VERSION 5.7 ;
  NOWIREEXTENSIONATPIN ON ;
  DIVIDERCHAR "/" ;
  BUSBITCHARS "[]" ;
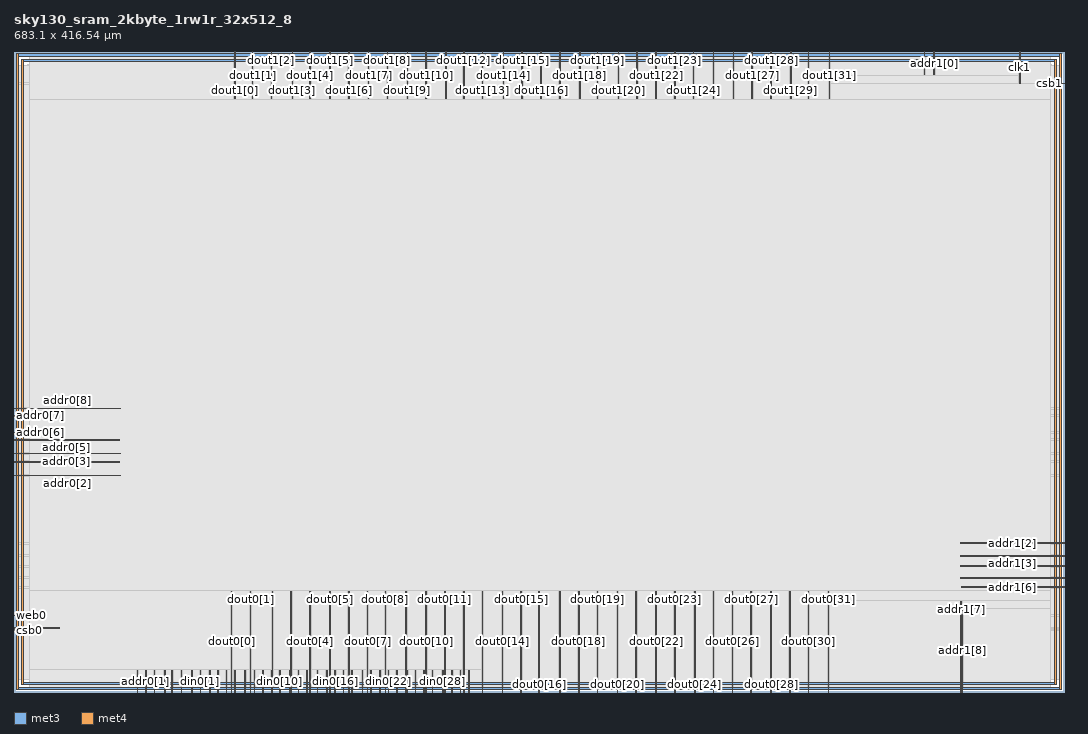
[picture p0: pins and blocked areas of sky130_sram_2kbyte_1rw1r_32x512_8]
MACRO sky130_sram_2kbyte_1rw1r_32x512_8
  CLASS BLOCK ;
  FOREIGN sky130_sram_2kbyte_1rw1r_32x512_8 ;
  ORIGIN 0.000 0.000 ;
  SIZE 683.100 BY 416.540 ;
  SYMMETRY X Y R90 ;
  PIN csb0
    DIRECTION INPUT ;
    ANTENNAGATEAREA 0.600000 ;
    PORT
      LAYER met3 ;
        RECT 0.000 40.120 14.660 40.500 ;
    END
  END csb0
  PIN web0
    DIRECTION INPUT ;
    ANTENNAGATEAREA 0.600000 ;
    PORT
      LAYER met3 ;
        RECT 0.000 49.640 14.660 50.020 ;
    END
  END web0
  PIN clk0
    DIRECTION INPUT ;
    ANTENNAGATEAREA 0.222000 ;
    PORT
      LAYER met3 ;
        RECT 0.000 41.480 29.875 41.860 ;
    END
  END clk0
  PIN addr0[2]
    DIRECTION INPUT ;
    ANTENNAGATEAREA 0.600000 ;
    PORT
      LAYER met3 ;
        RECT 0.000 140.760 69.060 141.140 ;
    END
  END addr0[2]
  PIN addr0[3]
    DIRECTION INPUT ;
    ANTENNAGATEAREA 0.600000 ;
    PORT
      LAYER met3 ;
        RECT 0.000 149.600 68.340 149.980 ;
    END
  END addr0[3]
  PIN addr0[4]
    DIRECTION INPUT ;
    ANTENNAGATEAREA 0.600000 ;
    PORT
      LAYER met3 ;
        RECT 0.000 155.040 69.060 155.420 ;
    END
  END addr0[4]
  PIN addr0[5]
    DIRECTION INPUT ;
    ANTENNAGATEAREA 0.600000 ;
    PORT
      LAYER met3 ;
        RECT 0.000 163.880 68.340 164.260 ;
    END
  END addr0[5]
  PIN addr0[6]
    DIRECTION INPUT ;
    ANTENNAGATEAREA 0.600000 ;
    PORT
      LAYER met3 ;
        RECT 0.000 168.640 10.580 169.020 ;
    END
  END addr0[6]
  PIN addr0[7]
    DIRECTION INPUT ;
    ANTENNAGATEAREA 0.600000 ;
    PORT
      LAYER met3 ;
        RECT 0.000 179.520 10.580 179.900 ;
    END
  END addr0[7]
  PIN addr0[8]
    DIRECTION INPUT ;
    ANTENNAGATEAREA 0.600000 ;
    PORT
      LAYER met3 ;
        RECT 0.000 184.280 69.060 184.660 ;
    END
  END addr0[8]
  PIN csb1
    DIRECTION INPUT ;
    ANTENNAGATEAREA 0.600000 ;
    PORT
      LAYER met3 ;
        RECT 669.700 395.760 683.100 396.140 ;
    END
  END csb1
  PIN addr1[2]
    DIRECTION INPUT ;
    ANTENNAGATEAREA 0.600000 ;
    PORT
      LAYER met3 ;
        RECT 616.080 96.560 683.100 96.940 ;
    END
  END addr1[2]
  PIN addr1[3]
    DIRECTION INPUT ;
    ANTENNAGATEAREA 0.600000 ;
    PORT
      LAYER met3 ;
        RECT 616.080 88.400 683.100 88.780 ;
    END
  END addr1[3]
  PIN addr1[4]
    DIRECTION INPUT ;
    ANTENNAGATEAREA 0.600000 ;
    PORT
      LAYER met3 ;
        RECT 616.080 81.600 683.100 81.980 ;
    END
  END addr1[4]
  PIN addr1[5]
    DIRECTION INPUT ;
    ANTENNAGATEAREA 0.600000 ;
    PORT
      LAYER met3 ;
        RECT 616.080 74.120 683.100 74.500 ;
    END
  END addr1[5]
  PIN addr1[6]
    DIRECTION INPUT ;
    ANTENNAGATEAREA 0.600000 ;
    PORT
      LAYER met3 ;
        RECT 616.630 68.000 683.100 68.380 ;
    END
  END addr1[6]
  PIN vccd1
    DIRECTION INOUT ;
    USE POWER ;
    SHAPE ABUTMENT ;
    PORT
      LAYER met3 ;
        RECT 4.760 410.040 678.340 411.780 ;
    END
    PORT
      LAYER met3 ;
        RECT 4.760 4.760 678.340 6.500 ;
    END
    PORT
      LAYER met4 ;
        RECT 4.760 4.760 6.500 411.780 ;
    END
    PORT
      LAYER met4 ;
        RECT 676.600 4.760 678.340 411.780 ;
    END
  END vccd1
  PIN vssd1
    DIRECTION INOUT ;
    USE GROUND ;
    SHAPE ABUTMENT ;
    PORT
      LAYER met3 ;
        RECT 1.360 1.360 681.740 3.100 ;
    END
    PORT
      LAYER met3 ;
        RECT 1.360 413.440 681.740 415.180 ;
    END
    PORT
      LAYER met4 ;
        RECT 1.360 1.360 3.100 415.180 ;
    END
    PORT
      LAYER met4 ;
        RECT 680.000 1.360 681.740 415.180 ;
    END
  END vssd1
  PIN clk1
    DIRECTION INPUT ;
    ANTENNAGATEAREA 0.222000 ;
    PORT
      LAYER met4 ;
        RECT 654.160 396.110 654.540 416.540 ;
    END
  END clk1
  PIN dout1[16]
    DIRECTION OUTPUT ;
    ANTENNADIFFAREA 0.553900 ;
    PORT
      LAYER met4 ;
        RECT 342.720 385.910 343.100 416.540 ;
    END
  END dout1[16]
  PIN dout1[17]
    DIRECTION OUTPUT ;
    ANTENNADIFFAREA 0.553900 ;
    PORT
      LAYER met4 ;
        RECT 354.960 385.910 355.340 416.540 ;
    END
  END dout1[17]
  PIN dout1[18]
    DIRECTION OUTPUT ;
    ANTENNADIFFAREA 0.553900 ;
    PORT
      LAYER met4 ;
        RECT 367.880 385.910 368.260 416.540 ;
    END
  END dout1[18]
  PIN dout1[19]
    DIRECTION OUTPUT ;
    ANTENNADIFFAREA 0.553900 ;
    PORT
      LAYER met4 ;
        RECT 379.440 385.910 379.820 416.540 ;
    END
  END dout1[19]
  PIN dout1[20]
    DIRECTION OUTPUT ;
    ANTENNADIFFAREA 0.553900 ;
    PORT
      LAYER met4 ;
        RECT 393.040 385.910 393.420 416.540 ;
    END
  END dout1[20]
  PIN dout1[21]
    DIRECTION OUTPUT ;
    ANTENNADIFFAREA 0.553900 ;
    PORT
      LAYER met4 ;
        RECT 405.280 385.910 405.660 416.540 ;
    END
  END dout1[21]
  PIN dout1[22]
    DIRECTION OUTPUT ;
    ANTENNADIFFAREA 0.553900 ;
    PORT
      LAYER met4 ;
        RECT 417.520 385.910 417.900 416.540 ;
    END
  END dout1[22]
  PIN dout1[23]
    DIRECTION OUTPUT ;
    ANTENNADIFFAREA 0.553900 ;
    PORT
      LAYER met4 ;
        RECT 429.760 385.910 430.140 416.540 ;
    END
  END dout1[23]
  PIN dout1[24]
    DIRECTION OUTPUT ;
    ANTENNADIFFAREA 0.553900 ;
    PORT
      LAYER met4 ;
        RECT 442.000 385.910 442.380 416.540 ;
    END
  END dout1[24]
  PIN dout1[25]
    DIRECTION OUTPUT ;
    ANTENNADIFFAREA 0.553900 ;
    PORT
      LAYER met4 ;
        RECT 454.920 385.910 455.300 416.540 ;
    END
  END dout1[25]
  PIN dout1[26]
    DIRECTION OUTPUT ;
    ANTENNADIFFAREA 0.553900 ;
    PORT
      LAYER met4 ;
        RECT 467.840 385.910 468.220 416.540 ;
    END
  END dout1[26]
  PIN dout1[27]
    DIRECTION OUTPUT ;
    ANTENNADIFFAREA 0.553900 ;
    PORT
      LAYER met4 ;
        RECT 480.080 385.910 480.460 416.540 ;
    END
  END dout1[27]
  PIN dout1[28]
    DIRECTION OUTPUT ;
    ANTENNADIFFAREA 0.553900 ;
    PORT
      LAYER met4 ;
        RECT 492.320 385.910 492.700 416.540 ;
    END
  END dout1[28]
  PIN dout1[29]
    DIRECTION OUTPUT ;
    ANTENNADIFFAREA 0.553900 ;
    PORT
      LAYER met4 ;
        RECT 505.240 385.910 505.620 416.540 ;
    END
  END dout1[29]
  PIN dout1[30]
    DIRECTION OUTPUT ;
    ANTENNADIFFAREA 0.553900 ;
    PORT
      LAYER met4 ;
        RECT 516.800 385.910 517.180 416.540 ;
    END
  END dout1[30]
  PIN dout1[31]
    DIRECTION OUTPUT ;
    ANTENNADIFFAREA 0.553900 ;
    PORT
      LAYER met4 ;
        RECT 530.400 385.910 530.780 416.540 ;
    END
  END dout1[31]
  PIN addr1[0]
    DIRECTION INPUT ;
    ANTENNAGATEAREA 0.600000 ;
    PORT
      LAYER met4 ;
        RECT 598.400 401.550 598.780 416.540 ;
    END
  END addr1[0]
  PIN addr1[1]
    DIRECTION INPUT ;
    ANTENNAGATEAREA 0.600000 ;
    PORT
      LAYER met4 ;
        RECT 592.280 401.550 592.660 416.540 ;
    END
  END addr1[1]
  PIN dout1[2]
    DIRECTION OUTPUT ;
    ANTENNADIFFAREA 0.553900 ;
    PORT
      LAYER met4 ;
        RECT 167.280 385.910 167.660 416.540 ;
    END
  END dout1[2]
  PIN dout1[3]
    DIRECTION OUTPUT ;
    ANTENNADIFFAREA 0.553900 ;
    PORT
      LAYER met4 ;
        RECT 180.880 385.910 181.260 416.540 ;
    END
  END dout1[3]
  PIN dout1[4]
    DIRECTION OUTPUT ;
    ANTENNADIFFAREA 0.553900 ;
    PORT
      LAYER met4 ;
        RECT 192.440 385.910 192.820 416.540 ;
    END
  END dout1[4]
  PIN dout1[5]
    DIRECTION OUTPUT ;
    ANTENNADIFFAREA 0.553900 ;
    PORT
      LAYER met4 ;
        RECT 205.360 385.910 205.740 416.540 ;
    END
  END dout1[5]
  PIN dout1[6]
    DIRECTION OUTPUT ;
    ANTENNADIFFAREA 0.553900 ;
    PORT
      LAYER met4 ;
        RECT 217.600 385.910 217.980 416.540 ;
    END
  END dout1[6]
  PIN dout1[7]
    DIRECTION OUTPUT ;
    ANTENNADIFFAREA 0.553900 ;
    PORT
      LAYER met4 ;
        RECT 230.520 385.910 230.900 416.540 ;
    END
  END dout1[7]
  PIN dout1[8]
    DIRECTION OUTPUT ;
    ANTENNADIFFAREA 0.553900 ;
    PORT
      LAYER met4 ;
        RECT 242.760 385.910 243.140 416.540 ;
    END
  END dout1[8]
  PIN dout1[9]
    DIRECTION OUTPUT ;
    ANTENNADIFFAREA 0.553900 ;
    PORT
      LAYER met4 ;
        RECT 255.680 385.910 256.060 416.540 ;
    END
  END dout1[9]
  PIN dout1[10]
    DIRECTION OUTPUT ;
    ANTENNADIFFAREA 0.553900 ;
    PORT
      LAYER met4 ;
        RECT 267.920 385.910 268.300 416.540 ;
    END
  END dout1[10]
  PIN dout1[11]
    DIRECTION OUTPUT ;
    ANTENNADIFFAREA 0.553900 ;
    PORT
      LAYER met4 ;
        RECT 280.840 385.910 281.220 416.540 ;
    END
  END dout1[11]
  PIN dout1[12]
    DIRECTION OUTPUT ;
    ANTENNADIFFAREA 0.553900 ;
    PORT
      LAYER met4 ;
        RECT 292.400 385.910 292.780 416.540 ;
    END
  END dout1[12]
  PIN dout1[13]
    DIRECTION OUTPUT ;
    ANTENNADIFFAREA 0.553900 ;
    PORT
      LAYER met4 ;
        RECT 304.640 385.910 305.020 416.540 ;
    END
  END dout1[13]
  PIN dout1[14]
    DIRECTION OUTPUT ;
    ANTENNADIFFAREA 0.553900 ;
    PORT
      LAYER met4 ;
        RECT 318.240 385.910 318.620 416.540 ;
    END
  END dout1[14]
  PIN dout1[15]
    DIRECTION OUTPUT ;
    ANTENNADIFFAREA 0.553900 ;
    PORT
      LAYER met4 ;
        RECT 330.480 385.910 330.860 416.540 ;
    END
  END dout1[15]
  PIN dout1[0]
    DIRECTION OUTPUT ;
    ANTENNADIFFAREA 0.553900 ;
    PORT
      LAYER met4 ;
        RECT 143.480 385.910 143.860 416.540 ;
    END
  END dout1[0]
  PIN dout1[1]
    DIRECTION OUTPUT ;
    ANTENNADIFFAREA 0.553900 ;
    PORT
      LAYER met4 ;
        RECT 155.040 385.910 155.420 416.540 ;
    END
  END dout1[1]
  PIN dout0[3]
    DIRECTION OUTPUT ;
    ANTENNADIFFAREA 0.553900 ;
    PORT
      LAYER met4 ;
        RECT 180.200 0.000 180.580 65.310 ;
    END
  END dout0[3]
  PIN dout0[4]
    DIRECTION OUTPUT ;
    ANTENNADIFFAREA 0.553900 ;
    PORT
      LAYER met4 ;
        RECT 192.440 0.000 192.820 65.310 ;
    END
  END dout0[4]
  PIN dout0[5]
    DIRECTION OUTPUT ;
    ANTENNADIFFAREA 0.553900 ;
    PORT
      LAYER met4 ;
        RECT 205.360 0.000 205.740 65.310 ;
    END
  END dout0[5]
  PIN dout0[6]
    DIRECTION OUTPUT ;
    ANTENNADIFFAREA 0.553900 ;
    PORT
      LAYER met4 ;
        RECT 217.600 0.000 217.980 65.310 ;
    END
  END dout0[6]
  PIN dout0[7]
    DIRECTION OUTPUT ;
    ANTENNADIFFAREA 0.553900 ;
    PORT
      LAYER met4 ;
        RECT 229.840 0.000 230.220 65.310 ;
    END
  END dout0[7]
  PIN dout0[8]
    DIRECTION OUTPUT ;
    ANTENNADIFFAREA 0.553900 ;
    PORT
      LAYER met4 ;
        RECT 241.400 0.000 241.780 65.310 ;
    END
  END dout0[8]
  PIN dout0[9]
    DIRECTION OUTPUT ;
    ANTENNADIFFAREA 0.553900 ;
    PORT
      LAYER met4 ;
        RECT 255.000 0.000 255.380 65.310 ;
    END
  END dout0[9]
  PIN dout0[10]
    DIRECTION OUTPUT ;
    ANTENNADIFFAREA 0.553900 ;
    PORT
      LAYER met4 ;
        RECT 267.920 0.000 268.300 65.310 ;
    END
  END dout0[10]
  PIN dout0[11]
    DIRECTION OUTPUT ;
    ANTENNADIFFAREA 0.553900 ;
    PORT
      LAYER met4 ;
        RECT 280.160 0.000 280.540 65.310 ;
    END
  END dout0[11]
  PIN dout0[12]
    DIRECTION OUTPUT ;
    ANTENNADIFFAREA 0.553900 ;
    PORT
      LAYER met4 ;
        RECT 292.400 0.000 292.780 65.310 ;
    END
  END dout0[12]
  PIN dout0[13]
    DIRECTION OUTPUT ;
    ANTENNADIFFAREA 0.553900 ;
    PORT
      LAYER met4 ;
        RECT 304.640 0.000 305.020 65.310 ;
    END
  END dout0[13]
  PIN dout0[14]
    DIRECTION OUTPUT ;
    ANTENNADIFFAREA 0.553900 ;
    PORT
      LAYER met4 ;
        RECT 317.560 0.000 317.940 65.310 ;
    END
  END dout0[14]
  PIN dout0[15]
    DIRECTION OUTPUT ;
    ANTENNADIFFAREA 0.553900 ;
    PORT
      LAYER met4 ;
        RECT 329.800 0.000 330.180 65.310 ;
    END
  END dout0[15]
  PIN dout0[16]
    DIRECTION OUTPUT ;
    ANTENNADIFFAREA 0.553900 ;
    PORT
      LAYER met4 ;
        RECT 341.360 0.000 341.740 65.310 ;
    END
  END dout0[16]
  PIN addr0[0]
    DIRECTION INPUT ;
    ANTENNAGATEAREA 0.600000 ;
    PORT
      LAYER met4 ;
        RECT 80.240 0.000 80.620 14.310 ;
    END
  END addr0[0]
  PIN addr0[1]
    DIRECTION INPUT ;
    ANTENNAGATEAREA 0.600000 ;
    PORT
      LAYER met4 ;
        RECT 85.680 0.000 86.060 14.310 ;
    END
  END addr0[1]
  PIN wmask0[0]
    DIRECTION INPUT ;
    ANTENNAGATEAREA 0.600000 ;
    PORT
      LAYER met4 ;
        RECT 91.120 0.000 91.500 14.310 ;
    END
  END wmask0[0]
  PIN wmask0[1]
    DIRECTION INPUT ;
    ANTENNAGATEAREA 0.600000 ;
    PORT
      LAYER met4 ;
        RECT 97.920 0.000 98.300 14.310 ;
    END
  END wmask0[1]
  PIN wmask0[2]
    DIRECTION INPUT ;
    ANTENNAGATEAREA 0.600000 ;
    PORT
      LAYER met4 ;
        RECT 102.680 0.000 103.060 14.310 ;
    END
  END wmask0[2]
  PIN wmask0[3]
    DIRECTION INPUT ;
    ANTENNAGATEAREA 0.600000 ;
    PORT
      LAYER met4 ;
        RECT 108.800 0.000 109.180 14.310 ;
    END
  END wmask0[3]
  PIN din0[0]
    DIRECTION INPUT ;
    ANTENNAGATEAREA 0.600000 ;
    PORT
      LAYER met4 ;
        RECT 115.600 0.000 115.980 14.310 ;
    END
  END din0[0]
  PIN din0[1]
    DIRECTION INPUT ;
    ANTENNAGATEAREA 0.600000 ;
    PORT
      LAYER met4 ;
        RECT 121.040 0.000 121.420 14.310 ;
    END
  END din0[1]
  PIN din0[2]
    DIRECTION INPUT ;
    ANTENNAGATEAREA 0.600000 ;
    PORT
      LAYER met4 ;
        RECT 127.160 0.000 127.540 14.310 ;
    END
  END din0[2]
  PIN din0[3]
    DIRECTION INPUT ;
    ANTENNAGATEAREA 0.600000 ;
    PORT
      LAYER met4 ;
        RECT 132.600 0.000 132.980 14.310 ;
    END
  END din0[3]
  PIN din0[4]
    DIRECTION INPUT ;
    ANTENNAGATEAREA 0.600000 ;
    PORT
      LAYER met4 ;
        RECT 138.040 0.000 138.420 14.310 ;
    END
  END din0[4]
  PIN din0[5]
    DIRECTION INPUT ;
    ANTENNAGATEAREA 0.600000 ;
    PORT
      LAYER met4 ;
        RECT 143.480 0.000 143.860 14.310 ;
    END
  END din0[5]
  PIN din0[6]
    DIRECTION INPUT ;
    ANTENNAGATEAREA 0.600000 ;
    PORT
      LAYER met4 ;
        RECT 150.280 0.000 150.660 14.310 ;
    END
  END din0[6]
  PIN din0[7]
    DIRECTION INPUT ;
    ANTENNAGATEAREA 0.600000 ;
    PORT
      LAYER met4 ;
        RECT 156.400 0.000 156.780 14.310 ;
    END
  END din0[7]
  PIN din0[8]
    DIRECTION INPUT ;
    ANTENNAGATEAREA 0.600000 ;
    PORT
      LAYER met4 ;
        RECT 161.840 0.000 162.220 14.310 ;
    END
  END din0[8]
  PIN din0[9]
    DIRECTION INPUT ;
    ANTENNAGATEAREA 0.600000 ;
    PORT
      LAYER met4 ;
        RECT 167.280 0.000 167.660 14.310 ;
    END
  END din0[9]
  PIN din0[10]
    DIRECTION INPUT ;
    ANTENNAGATEAREA 0.600000 ;
    PORT
      LAYER met4 ;
        RECT 172.720 0.000 173.100 14.310 ;
    END
  END din0[10]
  PIN din0[11]
    DIRECTION INPUT ;
    ANTENNAGATEAREA 0.600000 ;
    PORT
      LAYER met4 ;
        RECT 179.520 0.000 179.900 14.310 ;
    END
  END din0[11]
  PIN din0[12]
    DIRECTION INPUT ;
    ANTENNAGATEAREA 0.600000 ;
    PORT
      LAYER met4 ;
        RECT 184.960 0.000 185.340 14.310 ;
    END
  END din0[12]
  PIN din0[13]
    DIRECTION INPUT ;
    ANTENNAGATEAREA 0.600000 ;
    PORT
      LAYER met4 ;
        RECT 190.400 0.000 190.780 14.310 ;
    END
  END din0[13]
  PIN din0[14]
    DIRECTION INPUT ;
    ANTENNAGATEAREA 0.600000 ;
    PORT
      LAYER met4 ;
        RECT 197.200 0.000 197.580 14.310 ;
    END
  END din0[14]
  PIN din0[15]
    DIRECTION INPUT ;
    ANTENNAGATEAREA 0.600000 ;
    PORT
      LAYER met4 ;
        RECT 203.320 0.000 203.700 14.310 ;
    END
  END din0[15]
  PIN din0[16]
    DIRECTION INPUT ;
    ANTENNAGATEAREA 0.600000 ;
    PORT
      LAYER met4 ;
        RECT 208.760 0.000 209.140 14.310 ;
    END
  END din0[16]
  PIN din0[17]
    DIRECTION INPUT ;
    ANTENNAGATEAREA 0.600000 ;
    PORT
      LAYER met4 ;
        RECT 214.200 0.000 214.580 14.310 ;
    END
  END din0[17]
  PIN din0[18]
    DIRECTION INPUT ;
    ANTENNAGATEAREA 0.600000 ;
    PORT
      LAYER met4 ;
        RECT 219.640 0.000 220.020 14.310 ;
    END
  END din0[18]
  PIN din0[19]
    DIRECTION INPUT ;
    ANTENNAGATEAREA 0.600000 ;
    PORT
      LAYER met4 ;
        RECT 226.440 0.000 226.820 14.310 ;
    END
  END din0[19]
  PIN din0[20]
    DIRECTION INPUT ;
    ANTENNAGATEAREA 0.600000 ;
    PORT
      LAYER met4 ;
        RECT 231.880 0.000 232.260 14.310 ;
    END
  END din0[20]
  PIN din0[21]
    DIRECTION INPUT ;
    ANTENNAGATEAREA 0.600000 ;
    PORT
      LAYER met4 ;
        RECT 238.000 0.000 238.380 14.310 ;
    END
  END din0[21]
  PIN din0[22]
    DIRECTION INPUT ;
    ANTENNAGATEAREA 0.600000 ;
    PORT
      LAYER met4 ;
        RECT 243.440 0.000 243.820 14.310 ;
    END
  END din0[22]
  PIN din0[23]
    DIRECTION INPUT ;
    ANTENNAGATEAREA 0.600000 ;
    PORT
      LAYER met4 ;
        RECT 248.880 0.000 249.260 14.310 ;
    END
  END din0[23]
  PIN din0[24]
    DIRECTION INPUT ;
    ANTENNAGATEAREA 0.600000 ;
    PORT
      LAYER met4 ;
        RECT 255.680 0.000 256.060 14.310 ;
    END
  END din0[24]
  PIN din0[25]
    DIRECTION INPUT ;
    ANTENNAGATEAREA 0.600000 ;
    PORT
      LAYER met4 ;
        RECT 261.120 0.000 261.500 14.310 ;
    END
  END din0[25]
  PIN din0[26]
    DIRECTION INPUT ;
    ANTENNAGATEAREA 0.600000 ;
    PORT
      LAYER met4 ;
        RECT 266.560 0.000 266.940 14.310 ;
    END
  END din0[26]
  PIN din0[27]
    DIRECTION INPUT ;
    ANTENNAGATEAREA 0.600000 ;
    PORT
      LAYER met4 ;
        RECT 272.000 0.000 272.380 14.310 ;
    END
  END din0[27]
  PIN din0[28]
    DIRECTION INPUT ;
    ANTENNAGATEAREA 0.600000 ;
    PORT
      LAYER met4 ;
        RECT 278.800 0.000 279.180 14.310 ;
    END
  END din0[28]
  PIN din0[29]
    DIRECTION INPUT ;
    ANTENNAGATEAREA 0.600000 ;
    PORT
      LAYER met4 ;
        RECT 284.920 0.000 285.300 14.310 ;
    END
  END din0[29]
  PIN din0[30]
    DIRECTION INPUT ;
    ANTENNAGATEAREA 0.600000 ;
    PORT
      LAYER met4 ;
        RECT 290.360 0.000 290.740 14.310 ;
    END
  END din0[30]
  PIN din0[31]
    DIRECTION INPUT ;
    ANTENNAGATEAREA 0.600000 ;
    PORT
      LAYER met4 ;
        RECT 295.800 0.000 296.180 14.310 ;
    END
  END din0[31]
  PIN dout0[0]
    DIRECTION OUTPUT ;
    ANTENNADIFFAREA 0.553900 ;
    PORT
      LAYER met4 ;
        RECT 141.440 0.000 141.820 65.310 ;
    END
  END dout0[0]
  PIN dout0[1]
    DIRECTION OUTPUT ;
    ANTENNADIFFAREA 0.553900 ;
    PORT
      LAYER met4 ;
        RECT 153.680 0.000 154.060 65.310 ;
    END
  END dout0[1]
  PIN dout0[2]
    DIRECTION OUTPUT ;
    ANTENNADIFFAREA 0.553900 ;
    PORT
      LAYER met4 ;
        RECT 167.960 0.000 168.340 65.310 ;
    END
  END dout0[2]
  PIN dout0[30]
    DIRECTION OUTPUT ;
    ANTENNADIFFAREA 0.553900 ;
    PORT
      LAYER met4 ;
        RECT 516.800 0.000 517.180 65.310 ;
    END
  END dout0[30]
  PIN dout0[31]
    DIRECTION OUTPUT ;
    ANTENNADIFFAREA 0.553900 ;
    PORT
      LAYER met4 ;
        RECT 529.720 0.000 530.100 65.310 ;
    END
  END dout0[31]
  PIN dout0[17]
    DIRECTION OUTPUT ;
    ANTENNADIFFAREA 0.553900 ;
    PORT
      LAYER met4 ;
        RECT 354.960 0.000 355.340 65.310 ;
    END
  END dout0[17]
  PIN dout0[18]
    DIRECTION OUTPUT ;
    ANTENNADIFFAREA 0.553900 ;
    PORT
      LAYER met4 ;
        RECT 367.200 0.000 367.580 65.310 ;
    END
  END dout0[18]
  PIN dout0[19]
    DIRECTION OUTPUT ;
    ANTENNADIFFAREA 0.553900 ;
    PORT
      LAYER met4 ;
        RECT 379.440 0.000 379.820 65.310 ;
    END
  END dout0[19]
  PIN dout0[20]
    DIRECTION OUTPUT ;
    ANTENNADIFFAREA 0.553900 ;
    PORT
      LAYER met4 ;
        RECT 392.360 0.000 392.740 65.310 ;
    END
  END dout0[20]
  PIN dout0[21]
    DIRECTION OUTPUT ;
    ANTENNADIFFAREA 0.553900 ;
    PORT
      LAYER met4 ;
        RECT 404.600 0.000 404.980 65.310 ;
    END
  END dout0[21]
  PIN dout0[22]
    DIRECTION OUTPUT ;
    ANTENNADIFFAREA 0.553900 ;
    PORT
      LAYER met4 ;
        RECT 417.520 0.000 417.900 65.310 ;
    END
  END dout0[22]
  PIN dout0[23]
    DIRECTION OUTPUT ;
    ANTENNADIFFAREA 0.553900 ;
    PORT
      LAYER met4 ;
        RECT 429.760 0.000 430.140 65.310 ;
    END
  END dout0[23]
  PIN dout0[24]
    DIRECTION OUTPUT ;
    ANTENNADIFFAREA 0.553900 ;
    PORT
      LAYER met4 ;
        RECT 442.680 0.000 443.060 65.310 ;
    END
  END dout0[24]
  PIN dout0[25]
    DIRECTION OUTPUT ;
    ANTENNADIFFAREA 0.553900 ;
    PORT
      LAYER met4 ;
        RECT 454.920 0.000 455.300 65.310 ;
    END
  END dout0[25]
  PIN dout0[26]
    DIRECTION OUTPUT ;
    ANTENNADIFFAREA 0.553900 ;
    PORT
      LAYER met4 ;
        RECT 467.160 0.000 467.540 65.310 ;
    END
  END dout0[26]
  PIN dout0[27]
    DIRECTION OUTPUT ;
    ANTENNADIFFAREA 0.553900 ;
    PORT
      LAYER met4 ;
        RECT 479.400 0.000 479.780 65.310 ;
    END
  END dout0[27]
  PIN addr1[7]
    DIRECTION INPUT ;
    ANTENNAGATEAREA 0.600000 ;
    PORT
      LAYER met4 ;
        RECT 616.080 0.000 616.460 59.190 ;
    END
  END addr1[7]
  PIN addr1[8]
    DIRECTION INPUT ;
    ANTENNAGATEAREA 0.600000 ;
    PORT
      LAYER met4 ;
        RECT 616.760 0.000 617.140 53.750 ;
    END
  END addr1[8]
  PIN dout0[28]
    DIRECTION OUTPUT ;
    ANTENNADIFFAREA 0.553900 ;
    PORT
      LAYER met4 ;
        RECT 492.320 0.000 492.700 65.310 ;
    END
  END dout0[28]
  PIN dout0[29]
    DIRECTION OUTPUT ;
    ANTENNADIFFAREA 0.553900 ;
    PORT
      LAYER met4 ;
        RECT 504.560 0.000 504.940 65.310 ;
    END
  END dout0[29]
  OBS
      LAYER nwell ;
        RECT 8.690 8.200 674.780 407.785 ;
      LAYER li1 ;
        RECT 9.025 8.455 674.445 407.530 ;
      LAYER met1 ;
        RECT 8.550 8.060 674.920 407.925 ;
      LAYER met2 ;
        RECT 8.550 8.060 674.920 407.925 ;
      LAYER met3 ;
        RECT 2.720 396.540 680.380 407.700 ;
        RECT 2.720 395.360 669.300 396.540 ;
        RECT 2.720 185.060 680.380 395.360 ;
        RECT 69.460 183.880 680.380 185.060 ;
        RECT 2.720 180.300 680.380 183.880 ;
        RECT 10.980 179.120 680.380 180.300 ;
        RECT 2.720 169.420 680.380 179.120 ;
        RECT 10.980 168.240 680.380 169.420 ;
        RECT 2.720 164.660 680.380 168.240 ;
        RECT 68.740 163.480 680.380 164.660 ;
        RECT 2.720 155.820 680.380 163.480 ;
        RECT 69.460 154.640 680.380 155.820 ;
        RECT 2.720 150.380 680.380 154.640 ;
        RECT 68.740 149.200 680.380 150.380 ;
        RECT 2.720 141.540 680.380 149.200 ;
        RECT 69.460 140.360 680.380 141.540 ;
        RECT 2.720 97.340 680.380 140.360 ;
        RECT 2.720 96.160 615.680 97.340 ;
        RECT 2.720 89.180 680.380 96.160 ;
        RECT 2.720 88.000 615.680 89.180 ;
        RECT 2.720 82.380 680.380 88.000 ;
        RECT 2.720 81.200 615.680 82.380 ;
        RECT 2.720 74.900 680.380 81.200 ;
        RECT 2.720 73.720 615.680 74.900 ;
        RECT 2.720 68.780 680.380 73.720 ;
        RECT 2.720 67.600 616.230 68.780 ;
        RECT 2.720 50.420 680.380 67.600 ;
        RECT 15.060 49.240 680.380 50.420 ;
        RECT 2.720 42.260 680.380 49.240 ;
        RECT 30.275 41.080 680.380 42.260 ;
        RECT 2.720 40.900 680.380 41.080 ;
        RECT 15.060 39.720 680.380 40.900 ;
        RECT 2.720 8.160 680.380 39.720 ;
      LAYER met4 ;
        RECT 10.200 385.510 143.080 413.820 ;
        RECT 144.260 385.510 154.640 413.820 ;
        RECT 155.820 385.510 166.880 413.820 ;
        RECT 168.060 385.510 180.480 413.820 ;
        RECT 181.660 385.510 192.040 413.820 ;
        RECT 193.220 385.510 204.960 413.820 ;
        RECT 206.140 385.510 217.200 413.820 ;
        RECT 218.380 385.510 230.120 413.820 ;
        RECT 231.300 385.510 242.360 413.820 ;
        RECT 243.540 385.510 255.280 413.820 ;
        RECT 256.460 385.510 267.520 413.820 ;
        RECT 268.700 385.510 280.440 413.820 ;
        RECT 281.620 385.510 292.000 413.820 ;
        RECT 293.180 385.510 304.240 413.820 ;
        RECT 305.420 385.510 317.840 413.820 ;
        RECT 319.020 385.510 330.080 413.820 ;
        RECT 331.260 385.510 342.320 413.820 ;
        RECT 343.500 385.510 354.560 413.820 ;
        RECT 355.740 385.510 367.480 413.820 ;
        RECT 368.660 385.510 379.040 413.820 ;
        RECT 380.220 385.510 392.640 413.820 ;
        RECT 393.820 385.510 404.880 413.820 ;
        RECT 406.060 385.510 417.120 413.820 ;
        RECT 418.300 385.510 429.360 413.820 ;
        RECT 430.540 385.510 441.600 413.820 ;
        RECT 442.780 385.510 454.520 413.820 ;
        RECT 455.700 385.510 467.440 413.820 ;
        RECT 468.620 385.510 479.680 413.820 ;
        RECT 480.860 385.510 491.920 413.820 ;
        RECT 493.100 385.510 504.840 413.820 ;
        RECT 506.020 385.510 516.400 413.820 ;
        RECT 517.580 385.510 530.000 413.820 ;
        RECT 531.180 401.150 591.880 413.820 ;
        RECT 593.060 401.150 598.000 413.820 ;
        RECT 599.180 401.150 653.760 413.820 ;
        RECT 531.180 395.710 653.760 401.150 ;
        RECT 654.940 395.710 674.260 413.820 ;
        RECT 531.180 385.510 674.260 395.710 ;
        RECT 10.200 65.710 674.260 385.510 ;
        RECT 10.200 14.710 141.040 65.710 ;
        RECT 10.200 2.720 79.840 14.710 ;
        RECT 81.020 2.720 85.280 14.710 ;
        RECT 86.460 2.720 90.720 14.710 ;
        RECT 91.900 2.720 97.520 14.710 ;
        RECT 98.700 2.720 102.280 14.710 ;
        RECT 103.460 2.720 108.400 14.710 ;
        RECT 109.580 2.720 115.200 14.710 ;
        RECT 116.380 2.720 120.640 14.710 ;
        RECT 121.820 2.720 126.760 14.710 ;
        RECT 127.940 2.720 132.200 14.710 ;
        RECT 133.380 2.720 137.640 14.710 ;
        RECT 138.820 2.720 141.040 14.710 ;
        RECT 142.220 14.710 153.280 65.710 ;
        RECT 142.220 2.720 143.080 14.710 ;
        RECT 144.260 2.720 149.880 14.710 ;
        RECT 151.060 2.720 153.280 14.710 ;
        RECT 154.460 14.710 167.560 65.710 ;
        RECT 168.740 14.710 179.800 65.710 ;
        RECT 180.980 14.710 192.040 65.710 ;
        RECT 154.460 2.720 156.000 14.710 ;
        RECT 157.180 2.720 161.440 14.710 ;
        RECT 162.620 2.720 166.880 14.710 ;
        RECT 168.740 2.720 172.320 14.710 ;
        RECT 173.500 2.720 179.120 14.710 ;
        RECT 180.980 2.720 184.560 14.710 ;
        RECT 185.740 2.720 190.000 14.710 ;
        RECT 191.180 2.720 192.040 14.710 ;
        RECT 193.220 14.710 204.960 65.710 ;
        RECT 193.220 2.720 196.800 14.710 ;
        RECT 197.980 2.720 202.920 14.710 ;
        RECT 204.100 2.720 204.960 14.710 ;
        RECT 206.140 14.710 217.200 65.710 ;
        RECT 206.140 2.720 208.360 14.710 ;
        RECT 209.540 2.720 213.800 14.710 ;
        RECT 214.980 2.720 217.200 14.710 ;
        RECT 218.380 14.710 229.440 65.710 ;
        RECT 218.380 2.720 219.240 14.710 ;
        RECT 220.420 2.720 226.040 14.710 ;
        RECT 227.220 2.720 229.440 14.710 ;
        RECT 230.620 14.710 241.000 65.710 ;
        RECT 230.620 2.720 231.480 14.710 ;
        RECT 232.660 2.720 237.600 14.710 ;
        RECT 238.780 2.720 241.000 14.710 ;
        RECT 242.180 14.710 254.600 65.710 ;
        RECT 255.780 14.710 267.520 65.710 ;
        RECT 242.180 2.720 243.040 14.710 ;
        RECT 244.220 2.720 248.480 14.710 ;
        RECT 249.660 2.720 254.600 14.710 ;
        RECT 256.460 2.720 260.720 14.710 ;
        RECT 261.900 2.720 266.160 14.710 ;
        RECT 267.340 2.720 267.520 14.710 ;
        RECT 268.700 14.710 279.760 65.710 ;
        RECT 268.700 2.720 271.600 14.710 ;
        RECT 272.780 2.720 278.400 14.710 ;
        RECT 279.580 2.720 279.760 14.710 ;
        RECT 280.940 14.710 292.000 65.710 ;
        RECT 280.940 2.720 284.520 14.710 ;
        RECT 285.700 2.720 289.960 14.710 ;
        RECT 291.140 2.720 292.000 14.710 ;
        RECT 293.180 14.710 304.240 65.710 ;
        RECT 293.180 2.720 295.400 14.710 ;
        RECT 296.580 2.720 304.240 14.710 ;
        RECT 305.420 2.720 317.160 65.710 ;
        RECT 318.340 2.720 329.400 65.710 ;
        RECT 330.580 2.720 340.960 65.710 ;
        RECT 342.140 2.720 354.560 65.710 ;
        RECT 355.740 2.720 366.800 65.710 ;
        RECT 367.980 2.720 379.040 65.710 ;
        RECT 380.220 2.720 391.960 65.710 ;
        RECT 393.140 2.720 404.200 65.710 ;
        RECT 405.380 2.720 417.120 65.710 ;
        RECT 418.300 2.720 429.360 65.710 ;
        RECT 430.540 2.720 442.280 65.710 ;
        RECT 443.460 2.720 454.520 65.710 ;
        RECT 455.700 2.720 466.760 65.710 ;
        RECT 467.940 2.720 479.000 65.710 ;
        RECT 480.180 2.720 491.920 65.710 ;
        RECT 493.100 2.720 504.160 65.710 ;
        RECT 505.340 2.720 516.400 65.710 ;
        RECT 517.580 2.720 529.320 65.710 ;
        RECT 530.500 59.590 674.260 65.710 ;
        RECT 530.500 2.720 615.680 59.590 ;
        RECT 616.860 54.150 674.260 59.590 ;
        RECT 617.540 2.720 674.260 54.150 ;
  END
END sky130_sram_2kbyte_1rw1r_32x512_8
END LIBRARY

